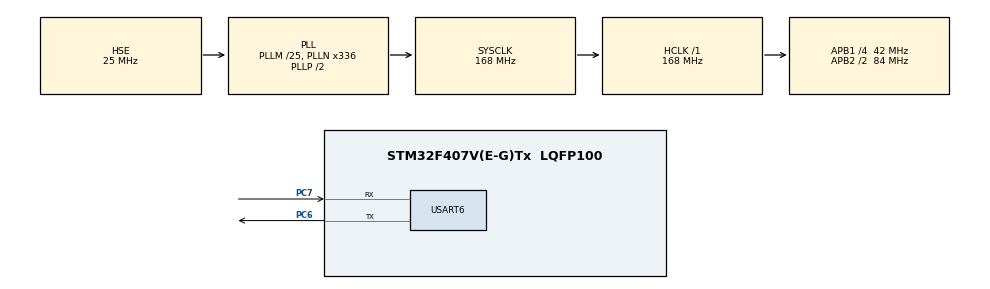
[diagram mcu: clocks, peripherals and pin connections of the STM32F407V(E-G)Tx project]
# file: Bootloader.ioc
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Mcu.Family=STM32F4
Mcu.Name=STM32F407V(E-G)Tx
Mcu.Package=LQFP100
NVIC.PriorityGroup=NVIC_PRIORITYGROUP_4
PA13.Mode=Serial_Wire
PA13.Signal=SYS_JTMS-SWDIO
PA14.Mode=Serial_Wire
PA14.Signal=SYS_JTCK-SWCLK
PC6.Mode=Asynchronous
PC6.Signal=USART6_TX
PC7.Mode=Asynchronous
PC7.Signal=USART6_RX
PH0-OSC_IN.Mode=HSE-External-Oscillator
PH0-OSC_IN.Signal=RCC_OSC_IN
PH1-OSC_OUT.Mode=HSE-External-Oscillator
PH1-OSC_OUT.Signal=RCC_OSC_OUT
ProjectManager.HeapSize=0x2000
ProjectManager.StackSize=0x4000
ProjectManager.TargetToolchain=TrueSTUDIO
RCC.48MHZClocksFreq_Value=84000000
RCC.AHBFreq_Value=168000000
RCC.APB1CLKDivider=RCC_HCLK_DIV4
RCC.APB1Freq_Value=42000000
RCC.APB1TimFreq_Value=84000000
RCC.APB2CLKDivider=RCC_HCLK_DIV2
RCC.APB2Freq_Value=84000000
RCC.APB2TimFreq_Value=168000000
RCC.CortexFreq_Value=168000000
RCC.HCLKFreq_Value=168000000
RCC.HSE_VALUE=25000000
RCC.HSI_VALUE=16000000
RCC.LSE_VALUE=32768
RCC.PLLM=25
RCC.PLLN=336
RCC.PLLSourceVirtual=RCC_PLLSOURCE_HSE
RCC.SYSCLKFreq_VALUE=168000000
RCC.SYSCLKSource=RCC_SYSCLKSOURCE_PLLCLK
RCC.VCOOutputFreq_Value=336000000
USART6.Parity=PARITY_EVEN
USART6.VirtualMode=VM_ASYNC
USART6.WordLength=WORDLENGTH_9B
board=Bootloader

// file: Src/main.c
/**
  ******************************************************************************
  * @file           : main.c
  * @brief          : Main program body
  ******************************************************************************
  ** This notice applies to any and all portions of this file
  * that are not between comment pairs USER CODE BEGIN and
  * USER CODE END. Other portions of this file, whether
  * inserted by the user or by software development tools
  * are owned by their respective copyright owners.
  *
  * COPYRIGHT(c) 2018 STMicroelectronics
  *
  * Redistribution and use in source and binary forms, with or without modification,
  * are permitted provided that the following conditions are met:
  *   1. Redistributions of source code must retain the above copyright notice,
  *      this list of conditions and the following disclaimer.
  *   2. Redistributions in binary form must reproduce the above copyright notice,
  *      this list of conditions and the following disclaimer in the documentation
  *      and/or other materials provided with the distribution.
  *   3. Neither the name of STMicroelectronics nor the names of its contributors
  *      may be used to endorse or promote products derived from this software
  *      without specific prior written permission.
  *
  * THIS SOFTWARE IS PROVIDED BY THE COPYRIGHT HOLDERS AND CONTRIBUTORS "AS IS"
  * AND ANY EXPRESS OR IMPLIED WARRANTIES, INCLUDING, BUT NOT LIMITED TO, THE
  * IMPLIED WARRANTIES OF MERCHANTABILITY AND FITNESS FOR A PARTICULAR PURPOSE ARE
  * DISCLAIMED. IN NO EVENT SHALL THE COPYRIGHT HOLDER OR CONTRIBUTORS BE LIABLE
  * FOR ANY DIRECT, INDIRECT, INCIDENTAL, SPECIAL, EXEMPLARY, OR CONSEQUENTIAL
  * DAMAGES (INCLUDING, BUT NOT LIMITED TO, PROCUREMENT OF SUBSTITUTE GOODS OR
  * SERVICES; LOSS OF USE, DATA, OR PROFITS; OR BUSINESS INTERRUPTION) HOWEVER
  * CAUSED AND ON ANY THEORY OF LIABILITY, WHETHER IN CONTRACT, STRICT LIABILITY,
  * OR TORT (INCLUDING NEGLIGENCE OR OTHERWISE) ARISING IN ANY WAY OUT OF THE USE
  * OF THIS SOFTWARE, EVEN IF ADVISED OF THE POSSIBILITY OF SUCH DAMAGE.
  *
  ******************************************************************************
  */
#include "main.h"
#include "stm32f4xx_hal.h"

/* USER CODE BEGIN Includes */
#include "Bootloader_Sketch.h"
/* USER CODE END Includes */

UART_HandleTypeDef huart6;

/* USER CODE BEGIN PV */
/* Private variables ---------------------------------------------------------*/
//change in linker script Debug/STM32F407VG_FLASH.ld to
//MEMORY
//{
//RAM (xrw)      : ORIGIN = 0x20000000, LENGTH = 128K
//CCMRAM (rw)      : ORIGIN = 0x10000000, LENGTH = 64K
//FLASH (rx)      : ORIGIN = 0x08000000, LENGTH = 16K
//}

//change the values in stm32f407xx.h to these
//#define FLASH_BASE            0x08000000U /*!< FLASH(up to 1 MB) base address in the alias region                         */
//#define CCMDATARAM_BASE       0x10000000U /*!< CCM(core coupled memory) data RAM(64 KB) base address in the alias region  */
//#define SRAM1_BASE            0x20000000U /*!< SRAM1(112 KB) base address in the alias region                              */
//#define SRAM2_BASE            0x2001C000U /*!< SRAM2(16 KB) base address in the alias region                              */
//#define PERIPH_BASE           0x40000000U /*!< Peripheral base address in the alias region                                */
//#define BKPSRAM_BASE          0x40024000U /*!< Backup SRAM(4 KB) base address in the alias region                         */
//#define FSMC_R_BASE           0xA0000000U /*!< FSMC registers base address                                                */
//#define SRAM1_BB_BASE         0x22000000U /*!< SRAM1(112 KB) base address in the bit-band region                          */
//#define SRAM2_BB_BASE         0x22380000U /*!< SRAM2(16 KB) base address in the bit-band region                           */
//#define PERIPH_BB_BASE        0x42000000U /*!< Peripheral base address in the bit-band region                             */
//#define BKPSRAM_BB_BASE       0x42480000U /*!< Backup SRAM(4 KB) base address in the bit-band region                      */
/* (FLASH_APPLICATION_SECTOR_ADDR(uint32_t)0x08004000 - 1)*/
//#define FLASH_END             0x08003FFFU /*!< FLASH end address                                                          */
//#define FLASH_OTP_BASE        0x1FFF7800U /*!< Base address of : (up to 528 Bytes) embedded FLASH OTP Area                */
//#define FLASH_OTP_END         0x1FFF7A0FU /*!< End address of : (up to 528 Bytes) embedded FLASH OTP Area                 */
//#define CCMDATARAM_END        0x1000FFFFU /*!< CCM data RAM end address                                                   */
/* USER CODE END PV */

void SystemClock_Config(void);
static void MX_GPIO_Init(void);
static void MX_USART6_UART_Init(void);

/* USER CODE BEGIN PFP */
/* Private function prototypes -----------------------------------------------*/

/* USER CODE END PFP */

int main(void)
{

  /* MCU Configuration----------------------------------------------------------*/

  /* Reset of all peripherals, Initializes the Flash interface and the Systick. */
  HAL_Init();

  /* Configure the system clock */
  SystemClock_Config();

  /* Initialize all configured peripherals */
  MX_GPIO_Init();
  MX_USART6_UART_Init();
  /* USER CODE BEGIN 2 */
	__enable_irq();
	Bootloader_Init(&huart6);
  /* USER CODE END 2 */

  /* Infinite loop */
  while (1)
  {

  /* USER CODE BEGIN 3 */
	Bootloader_Loop();
  }
  /* USER CODE END 3 */

}

void SystemClock_Config(void)
{

  RCC_OscInitTypeDef RCC_OscInitStruct;
  RCC_ClkInitTypeDef RCC_ClkInitStruct;

    /**Configure the main internal regulator output voltage
    */
  __HAL_RCC_PWR_CLK_ENABLE();

  __HAL_PWR_VOLTAGESCALING_CONFIG(PWR_REGULATOR_VOLTAGE_SCALE1);

    /**Initializes the CPU, AHB and APB busses clocks
    */
  RCC_OscInitStruct.OscillatorType = RCC_OSCILLATORTYPE_HSE;
  RCC_OscInitStruct.HSEState = RCC_HSE_ON;
  RCC_OscInitStruct.PLL.PLLState = RCC_PLL_ON;
  RCC_OscInitStruct.PLL.PLLSource = RCC_PLLSOURCE_HSE;
  RCC_OscInitStruct.PLL.PLLM = 25;
  RCC_OscInitStruct.PLL.PLLN = 336;
  RCC_OscInitStruct.PLL.PLLP = RCC_PLLP_DIV2;
  RCC_OscInitStruct.PLL.PLLQ = 4;
  if (HAL_RCC_OscConfig(&RCC_OscInitStruct) != HAL_OK)
  {
    _Error_Handler(__FILE__, __LINE__);
  }

    /**Initializes the CPU, AHB and APB busses clocks
    */
  RCC_ClkInitStruct.ClockType = RCC_CLOCKTYPE_HCLK|RCC_CLOCKTYPE_SYSCLK
                              |RCC_CLOCKTYPE_PCLK1|RCC_CLOCKTYPE_PCLK2;
  RCC_ClkInitStruct.SYSCLKSource = RCC_SYSCLKSOURCE_PLLCLK;
  RCC_ClkInitStruct.AHBCLKDivider = RCC_SYSCLK_DIV1;
  RCC_ClkInitStruct.APB1CLKDivider = RCC_HCLK_DIV4;
  RCC_ClkInitStruct.APB2CLKDivider = RCC_HCLK_DIV2;

  if (HAL_RCC_ClockConfig(&RCC_ClkInitStruct, FLASH_LATENCY_5) != HAL_OK)
  {
    _Error_Handler(__FILE__, __LINE__);
  }

    /**Configure the Systick interrupt time
    */
  HAL_SYSTICK_Config(HAL_RCC_GetHCLKFreq()/1000);

    /**Configure the Systick
    */
  HAL_SYSTICK_CLKSourceConfig(SYSTICK_CLKSOURCE_HCLK);

  /* SysTick_IRQn interrupt configuration */
  HAL_NVIC_SetPriority(SysTick_IRQn, 0, 0);
}

/* USART6 init function */
static void MX_USART6_UART_Init(void)
{

  huart6.Instance = USART6;
  huart6.Init.BaudRate = 115200;
  huart6.Init.WordLength = UART_WORDLENGTH_9B;
  huart6.Init.StopBits = UART_STOPBITS_1;
  huart6.Init.Parity = UART_PARITY_EVEN;
  huart6.Init.Mode = UART_MODE_TX_RX;
  huart6.Init.HwFlowCtl = UART_HWCONTROL_NONE;
  huart6.Init.OverSampling = UART_OVERSAMPLING_16;
  if (HAL_UART_Init(&huart6) != HAL_OK)
  {
    _Error_Handler(__FILE__, __LINE__);
  }

}

/** Configure pins as
        * Analog
        * Input
        * Output
        * EVENT_OUT
        * EXTI
        * Free pins are configured automatically as Analog (this feature is enabled through
        * the Code Generation settings)
*/
static void MX_GPIO_Init(void)
{

	  GPIO_InitTypeDef GPIO_InitStruct;

	  /* GPIO Ports Clock Enable */
	  __HAL_RCC_GPIOE_CLK_ENABLE();
	  __HAL_RCC_GPIOC_CLK_ENABLE();
	  __HAL_RCC_GPIOH_CLK_ENABLE();
	  __HAL_RCC_GPIOA_CLK_ENABLE();
	  __HAL_RCC_GPIOB_CLK_ENABLE();
	  __HAL_RCC_GPIOD_CLK_ENABLE();

	  /*Configure GPIO pin Output Level */
	  HAL_GPIO_WritePin(GPIOE, LEDR4_Pin|LEDG4_Pin|LEDR3_Pin|LEDG3_Pin
	                          |LEDR2_Pin|LEDR5_Pin|LEDG5_Pin, GPIO_PIN_RESET);

	  /*Configure GPIO pin Output Level */
	  HAL_GPIO_WritePin(GPIOC, LEDG2_Pin|LEDR1_Pin|LEDG1_Pin, GPIO_PIN_RESET);

	  /*Configure GPIO pins : LEDR4_Pin LEDG4_Pin LEDR3_Pin LEDG3_Pin
	                           LEDR2_Pin LEDR5_Pin LEDG5_Pin */
	  GPIO_InitStruct.Pin = LEDR4_Pin|LEDG4_Pin|LEDR3_Pin|LEDG3_Pin
	                          |LEDR2_Pin|LEDR5_Pin|LEDG5_Pin;
	  GPIO_InitStruct.Mode = GPIO_MODE_OUTPUT_PP;
	  GPIO_InitStruct.Pull = GPIO_NOPULL;
	  GPIO_InitStruct.Speed = GPIO_SPEED_FREQ_LOW;
	  HAL_GPIO_Init(GPIOE, &GPIO_InitStruct);

	  /*Configure GPIO pins : PC13 PC14 PC15 PC1
	                           PC4 PC5 PC8 PC9
	                           PC10 PC11 PC12 */
	  GPIO_InitStruct.Pin = GPIO_PIN_13|GPIO_PIN_14|GPIO_PIN_15|GPIO_PIN_1
	                          |GPIO_PIN_4|GPIO_PIN_5|GPIO_PIN_8|GPIO_PIN_9
	                          |GPIO_PIN_10|GPIO_PIN_11|GPIO_PIN_12;
	  GPIO_InitStruct.Mode = GPIO_MODE_ANALOG;
	  GPIO_InitStruct.Pull = GPIO_NOPULL;
	  HAL_GPIO_Init(GPIOC, &GPIO_InitStruct);

	  /*Configure GPIO pins : LEDG2_Pin LEDR1_Pin LEDG1_Pin */
	  GPIO_InitStruct.Pin = LEDG2_Pin|LEDR1_Pin|LEDG1_Pin;
	  GPIO_InitStruct.Mode = GPIO_MODE_OUTPUT_PP;
	  GPIO_InitStruct.Pull = GPIO_NOPULL;
	  GPIO_InitStruct.Speed = GPIO_SPEED_FREQ_LOW;
	  HAL_GPIO_Init(GPIOC, &GPIO_InitStruct);

	  /*Configure GPIO pins : PA0 PA1 PA2 PA3
	                           PA4 PA5 PA6 PA7
	                           PA8 PA9 PA10 PA11
	                           PA12 PA15 */
	  GPIO_InitStruct.Pin = GPIO_PIN_0|GPIO_PIN_1|GPIO_PIN_2|GPIO_PIN_3
	                          |GPIO_PIN_4|GPIO_PIN_5|GPIO_PIN_6|GPIO_PIN_7
	                          |GPIO_PIN_8|GPIO_PIN_9|GPIO_PIN_10|GPIO_PIN_11
	                          |GPIO_PIN_12|GPIO_PIN_15;
	  GPIO_InitStruct.Mode = GPIO_MODE_ANALOG;
	  GPIO_InitStruct.Pull = GPIO_NOPULL;
	  HAL_GPIO_Init(GPIOA, &GPIO_InitStruct);

	  /*Configure GPIO pins : PB0 PB1 PB2 PB10
	                           PB11 PB12 PB13 PB14
	                           PB15 PB3 PB4 PB5
	                           PB6 PB7 PB8 PB9 */
	  GPIO_InitStruct.Pin = GPIO_PIN_0|GPIO_PIN_1|GPIO_PIN_2|GPIO_PIN_10
	                          |GPIO_PIN_11|GPIO_PIN_12|GPIO_PIN_13|GPIO_PIN_14
	                          |GPIO_PIN_15|GPIO_PIN_3|GPIO_PIN_4|GPIO_PIN_5
	                          |GPIO_PIN_6|GPIO_PIN_7|GPIO_PIN_8|GPIO_PIN_9;
	  GPIO_InitStruct.Mode = GPIO_MODE_ANALOG;
	  GPIO_InitStruct.Pull = GPIO_NOPULL;
	  HAL_GPIO_Init(GPIOB, &GPIO_InitStruct);

	  /*Configure GPIO pins : PE7 PE8 PE9 PE10
	                           PE11 PE12 PE13 PE14
	                           PE15 */
	  GPIO_InitStruct.Pin = GPIO_PIN_7|GPIO_PIN_8|GPIO_PIN_9|GPIO_PIN_10
	                          |GPIO_PIN_11|GPIO_PIN_12|GPIO_PIN_13|GPIO_PIN_14
	                          |GPIO_PIN_15;
	  GPIO_InitStruct.Mode = GPIO_MODE_ANALOG;
	  GPIO_InitStruct.Pull = GPIO_NOPULL;
	  HAL_GPIO_Init(GPIOE, &GPIO_InitStruct);

	  /*Configure GPIO pins : PD8 PD9 PD10 PD11
	                           PD12 PD13 PD14 PD15
	                           PD0 PD1 PD2 PD3
	                           PD4 PD5 PD6 PD7 */
	  GPIO_InitStruct.Pin = GPIO_PIN_8|GPIO_PIN_9|GPIO_PIN_10|GPIO_PIN_11
	                          |GPIO_PIN_12|GPIO_PIN_13|GPIO_PIN_14|GPIO_PIN_15
	                          |GPIO_PIN_0|GPIO_PIN_1|GPIO_PIN_2|GPIO_PIN_3
	                          |GPIO_PIN_4|GPIO_PIN_5|GPIO_PIN_6|GPIO_PIN_7;
	  GPIO_InitStruct.Mode = GPIO_MODE_ANALOG;
	  GPIO_InitStruct.Pull = GPIO_NOPULL;
	  HAL_GPIO_Init(GPIOD, &GPIO_InitStruct);

}

void _Error_Handler(char *file, int line)
{
  while(1)
  {
  }
}

/************************ (C) COPYRIGHT STMicroelectronics *****END OF FILE****/
